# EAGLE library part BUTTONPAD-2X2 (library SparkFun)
5mm Button Pad Proven layout and schematic for 2x2 button pad. Panelize this device/fp to a 4x4 pad if needed. Spark Fun Electronics SKU : COM-07835. Compatible common cathode tri-color LED SKU : COM-00105

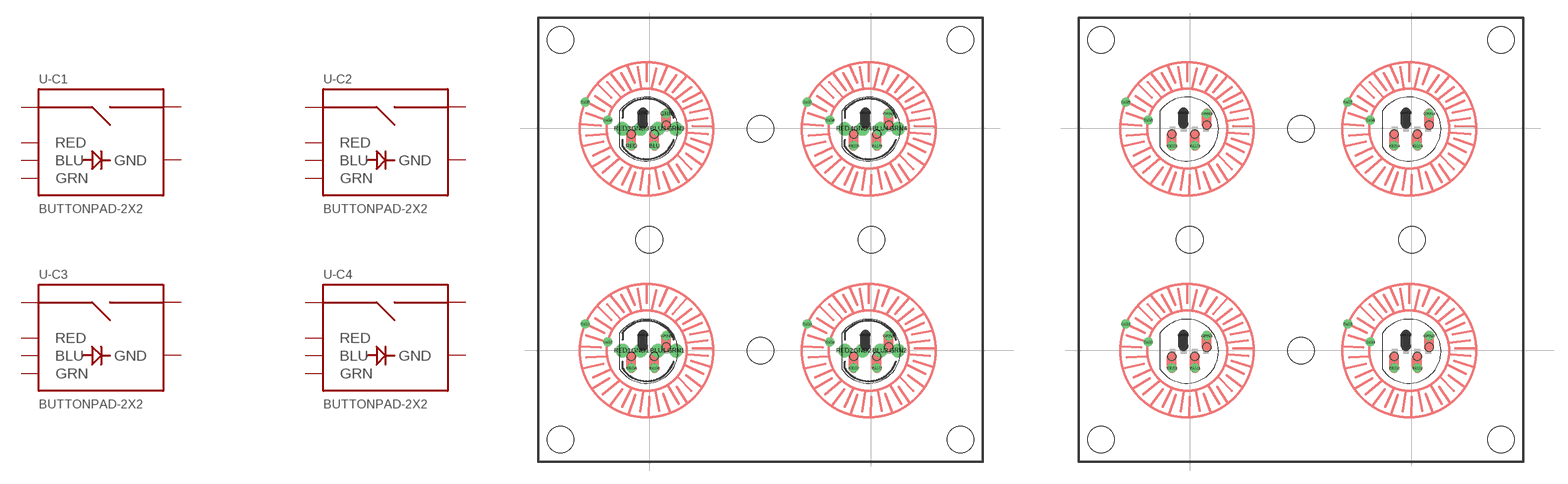
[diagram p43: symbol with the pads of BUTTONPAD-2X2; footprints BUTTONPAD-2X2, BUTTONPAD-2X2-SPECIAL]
Designator prefix -; gates -C1=BUTTONPAD_SINGLE -C2=BUTTONPAD_SINGLE -C3=BUTTONPAD_SINGLE -C4=BUTTONPAD_SINGLE

## BUTTONPAD-2X2  [BUTTONPAD-2X2]
BLU1  -C1:BLU
BLU2  -C2:BLU
BLU3  -C3:BLU
BLU4  -C4:BLU
GND1  -C1:GND
GND2  -C2:GND
GND3  -C3:GND
GND4  -C4:GND
GRN1  -C1:GRN
GRN2  -C2:GRN
GRN3  -C3:GRN
GRN4  -C4:GRN
RED1  -C1:RED
RED2  -C2:RED
RED3  -C3:RED
RED4  -C4:RED
SIG1  -C1:SIG1
SIG2  -C1:SIG2
SIG3  -C2:SIG1
SIG4  -C2:SIG2
SIG5  -C3:SIG1
SIG6  -C3:SIG2
SIG7  -C4:SIG1
SIG8  -C4:SIG2

## BUTTONPAD-2X2-SPECIAL  [BUTTONPAD-2X2-SPECIAL]
Pads as for BUTTONPAD-2X2

## Footprint BUTTONPAD-2X2 (pad centres in mm)
drill 0.508 round: BLU 13.081,35.585; BLU5 38.1,35.585; BLU6 13.081,10.566; BLU7 38.1,10.566; GND 11.786,39.319; GND5 36.805,39.319; GND6 11.786,14.3; GND7 36.805,14.3; GRN 14.427,39.218; GRN5 39.446,39.218; GRN6 14.427,14.199; GRN7 39.446,14.199; RED 10.49,35.585; RED5 35.509,35.585; RED6 10.49,10.566; RED7 35.509,10.566; SIG1 5.288,15.513; SIG2 7.828,13.481; SIG3 30.288,15.513; SIG4 32.828,13.481; SIG5 5.288,40.513; SIG6 7.828,38.481; SIG7 30.288,40.513; SIG8 32.828,38.481
drill 1 round: BLU1 13.5,12.5; BLU2 38.5,12.5; BLU3 13.5,37.5; BLU4 38.5,37.5; GND1 11.5,12.5; GND2 36.5,12.5; GND3 11.5,37.5; GND4 36.5,37.5; GRN1 15.5,12.5; GRN2 40.5,12.5; GRN3 15.5,37.5; GRN4 40.5,37.5; RED1 9.5,12.5; RED2 34.5,12.5; RED3 9.5,37.5; RED4 34.5,37.5
hole 3 at 12.5,25
hole 3 at 25,37.5
hole 3 at 37.5,25
hole 3 at 25,12.5
hole 3 at 2.5,2.5
hole 3 at 2.5,47.5
hole 3 at 47.5,47.5
hole 3 at 47.5,2.5
hole 0.914 at 10.49,36.881
hole 0.914 at 11.786,38.024
hole 0.914 at 13.081,36.881
hole 0.914 at 14.427,37.922
hole 0.914 at 35.509,36.881
hole 0.914 at 36.805,38.024
hole 0.914 at 38.1,36.881
hole 0.914 at 39.446,37.922
hole 0.914 at 10.49,11.862
hole 0.914 at 11.786,13.005
hole 0.914 at 13.081,11.862
hole 0.914 at 14.427,12.903
hole 0.914 at 35.509,11.862
hole 0.914 at 36.805,13.005
hole 0.914 at 38.1,11.862
hole 0.914 at 39.446,12.903

## Footprint BUTTONPAD-2X2-SPECIAL (pad centres in mm)
drill 0.508 round: BLU1 13.081,10.566; BLU2 38.1,10.566; BLU3 13.081,35.585; BLU4 38.1,35.585; GND1 11.786,14.3; GND2 36.805,14.3; GND3 11.786,39.319; GND4 36.805,39.319; GRN1 14.427,14.199; GRN2 39.446,14.199; GRN3 14.427,39.218; GRN4 39.446,39.218; RED1 10.49,10.566; RED2 35.509,10.566; RED3 10.49,35.585; RED4 35.509,35.585; SIG1 5.288,15.513; SIG2 7.828,13.481; SIG3 30.288,15.513; SIG4 32.828,13.481; SIG5 5.288,40.513; SIG6 7.828,38.481; SIG7 30.288,40.513; SIG8 32.828,38.481
hole 3 at 12.5,25
hole 3 at 25,37.5
hole 3 at 37.5,25
hole 3 at 25,12.5
hole 3 at 2.5,2.5
hole 3 at 2.5,47.5
hole 3 at 47.5,47.5
hole 3 at 47.5,2.5
hole 0.914 at 10.49,36.881
hole 0.914 at 11.786,38.024
hole 0.914 at 13.081,36.881
hole 0.914 at 14.427,37.922
hole 0.914 at 35.509,36.881
hole 0.914 at 36.805,38.024
hole 0.914 at 38.1,36.881
hole 0.914 at 39.446,37.922
hole 0.914 at 10.49,11.862
hole 0.914 at 11.786,13.005
hole 0.914 at 13.081,11.862
hole 0.914 at 14.427,12.903
hole 0.914 at 35.509,11.862
hole 0.914 at 36.805,13.005
hole 0.914 at 38.1,11.862
hole 0.914 at 39.446,12.903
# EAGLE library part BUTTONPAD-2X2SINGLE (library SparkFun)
5mm Button Pad Proto layout and schematic for 2x2 button pad with single color LEDs (used on Simon board). Panelize this device/fp to a 4x4 pad if needed. Any single-color 5mm LED should be compatible. Spark Fun Electronics SKU : COM-07835.

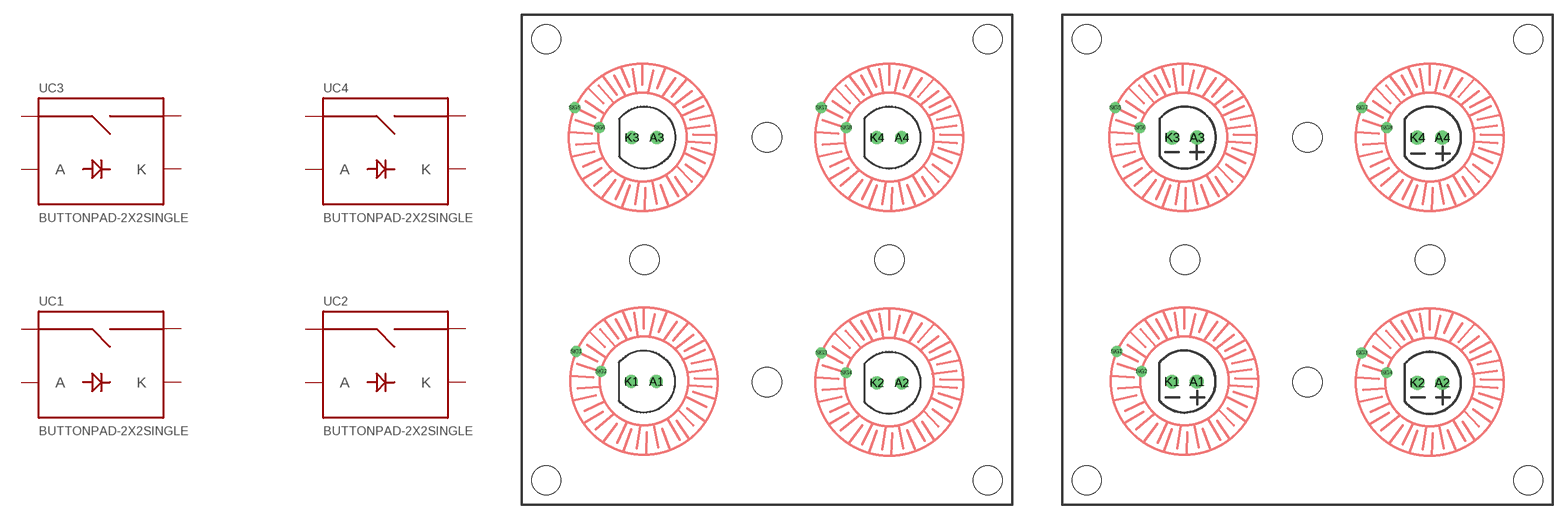
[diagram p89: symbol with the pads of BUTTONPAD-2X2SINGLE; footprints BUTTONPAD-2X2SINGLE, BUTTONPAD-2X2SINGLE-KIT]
Designator prefix -; gates C1=BUTTONPAD_1LED C2=BUTTONPAD_1LED C3=BUTTONPAD_1LED C4=BUTTONPAD_1LED

## BUTTONPAD-2X2SINGLE  [BUTTONPAD-2X2SINGLE]
A1  C1:A
A2  C2:A
A3  C3:A
A4  C4:A
K1  C1:K
K2  C2:K
K3  C3:K
K4  C4:K
SIG1  C1:SIG1
SIG2  C1:SIG2
SIG3  C2:SIG1
SIG4  C2:SIG2
SIG5  C3:SIG1
SIG6  C3:SIG2
SIG7  C4:SIG1
SIG8  C4:SIG2

## BUTTONPAD-2X2SINGLEKIT  [BUTTONPAD-2X2SINGLE-KIT]
Pads as for BUTTONPAD-2X2SINGLE

## Footprint BUTTONPAD-2X2SINGLE (pad centres in mm)
drill 0.813 round: A1 13.716,12.573; A2 38.735,12.446; A3 13.75,37.47; A4 38.735,37.465; K1 11.176,12.573; K2 36.195,12.446; K3 11.21,37.47; K4 36.195,37.465
drill 0.6 round: SIG1 5.542,15.64; SIG2 8.082,13.608; SIG3 30.542,15.513; SIG4 33.082,13.481; SIG5 5.388,40.513; SIG6 7.928,38.481; SIG7 30.542,40.513; SIG8 33.082,38.481
hole 3 at 12.5,25
hole 3 at 25,37.5
hole 3 at 37.5,25
hole 3 at 25,12.5
hole 3 at 2.5,2.5
hole 3 at 2.5,47.5
hole 3 at 47.5,47.5
hole 3 at 47.5,2.5

## Footprint BUTTONPAD-2X2SINGLE-KIT (pad centres in mm)
BUTTONPAD-2X2SINGLE-KIT Warning: This is the KIT version of this package. This package has a smaller diameter top stop mask, which doesn't cover the diameter of the pad. This means only the bottom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
drill 0.889 pad 1.016 round: A1 13.716,12.573; A2 38.735,12.446; A3 13.75,37.47; A4 38.735,37.465; K1 11.176,12.573; K2 36.195,12.446; K3 11.21,37.47; K4 36.195,37.465
drill 0.6 round: SIG1 5.542,15.64; SIG2 8.082,13.608; SIG3 30.542,15.513; SIG4 33.082,13.481; SIG5 5.388,40.513; SIG6 7.928,38.481; SIG7 30.542,40.513; SIG8 33.082,38.481
hole 3 at 12.5,25
hole 3 at 25,37.5
hole 3 at 37.5,25
hole 3 at 25,12.5
hole 3 at 2.5,2.5
hole 3 at 2.5,47.5
hole 3 at 47.5,47.5
hole 3 at 47.5,2.5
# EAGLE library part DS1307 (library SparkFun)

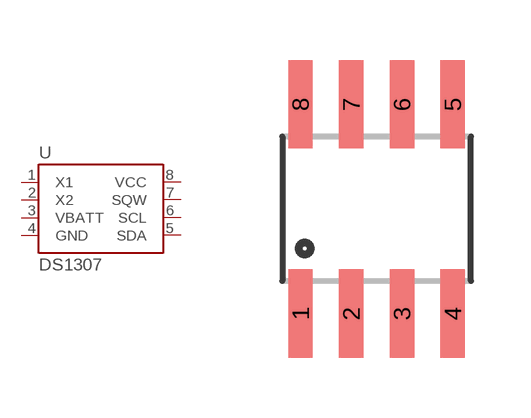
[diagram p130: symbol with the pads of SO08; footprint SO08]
Designator prefix -

## DS1307SO8  [SO08]
1  X1
2  X2
3  VBATT
4  GND
5  SDA
6  SCL
7  SQW
8  VCC

## Footprint SO08 (pad centres in mm)
Small Outline Package Fits JEDEC packages (narrow SOIC-8)
smd 0.61 x 2.21: 1 -1.905,-2.616; 2 -0.635,-2.616; 3 0.635,-2.616; 4 1.905,-2.616; 5 1.905,2.616; 6 0.635,2.616; 7 -0.635,2.616; 8 -1.905,2.616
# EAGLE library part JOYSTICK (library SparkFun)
Thumb Joystick Joystick commonly found in PS2 controllers. Two pots and a select switch. Footprint proven. Spark Fun Electronics SKU : COM-09032

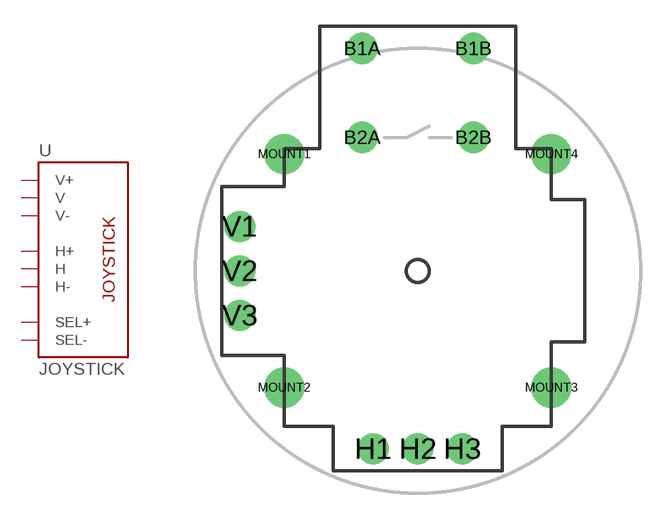
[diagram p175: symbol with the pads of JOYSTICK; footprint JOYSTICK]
Designator prefix U

## JOYSTICKPTH  [JOYSTICK]
B1A  SEL+
B2A  SEL-
H1  H+
H2  H
H3  H-
V1  V+
V2  V
V3  V-

## Footprint JOYSTICK (pad centres in mm)
drill 0.9 pad 1.778 round: B1A -3.175,12.7; B1B 3.175,12.7; B2A -3.175,7.62; B2B 3.175,7.62
drill 0.889 pad 1.778 round: H1 -2.54,-10.16; H2 0,-10.16; H3 2.54,-10.16; V1 -10.16,2.54; V2 -10.16,0; V3 -10.16,-2.54
drill 1.397 pad 2.286 round: MOUNT1 -7.62,6.668; MOUNT2 -7.62,-6.668; MOUNT3 7.62,-6.668; MOUNT4 7.62,6.668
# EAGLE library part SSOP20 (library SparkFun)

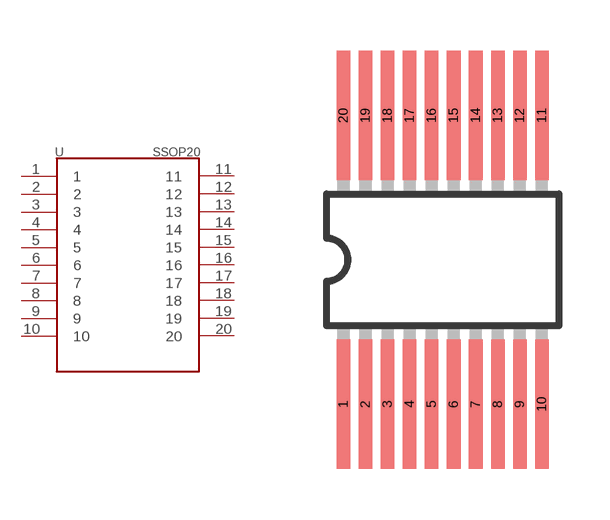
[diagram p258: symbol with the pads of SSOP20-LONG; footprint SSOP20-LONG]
Designator prefix -

## SSOP20  [SSOP20-LONG]
1  1
2  2
3  3
4  4
5  5
6  6
7  7
8  8
9  9
10  10
11  11
12  12
13  13
14  14
15  15
16  16
17  17
18  18
19  19
20  20

## Footprint SSOP20-LONG (pad centres in mm)
SSOP-20PIN Do Not Use as this is for the silkscreen of the breakout board for 20pin-SSOP ICs
smd 0.4 x 3.81: 1 -2.925,-4.26; 2 -2.275,-4.26; 3 -1.625,-4.26; 4 -0.975,-4.26; 5 -0.325,-4.26; 6 0.325,-4.26; 7 0.975,-4.26; 8 1.625,-4.26; 9 2.275,-4.26; 10 2.925,-4.26; 11 2.925,4.26; 12 2.275,4.26; 13 1.625,4.26; 14 0.975,4.26; 15 0.325,4.26; 16 -0.325,4.26; 17 -0.975,4.26; 18 -1.625,4.26; 19 -2.275,4.26; 20 -2.925,4.26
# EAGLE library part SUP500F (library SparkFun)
SUP500F Venus GPS

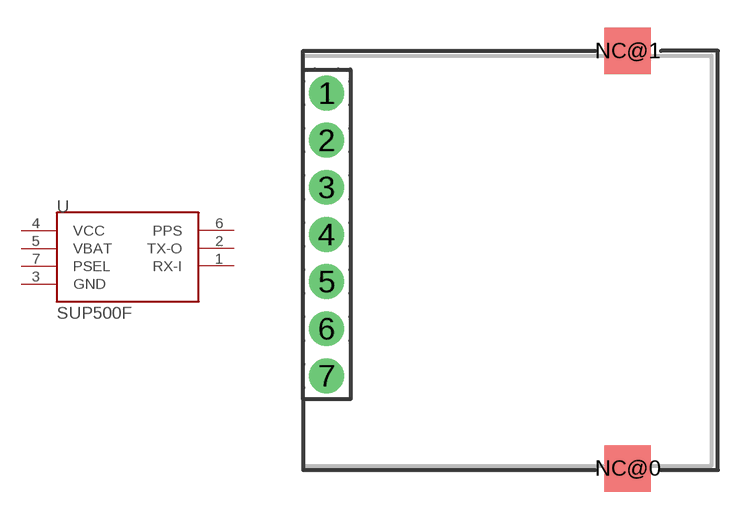
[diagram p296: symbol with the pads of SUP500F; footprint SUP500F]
Designator prefix U

## SUP500F  [SUP500F]
1  RX-I
2  TX-O
3  GND
4  VCC
5  VBAT
6  PPS
7  PSEL

## Footprint SUP500F (pad centres in mm)
drill 1.016 pad 1.88 round: 1 0,15.24; 2 0,12.7; 3 0,10.16; 4 0,7.62; 5 0,5.08; 6 0,2.54; 7 0,0
smd 2.5 x 2.5: NC@0 16.22,-5; NC@1 16.22,17.51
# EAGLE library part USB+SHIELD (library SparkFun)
USB+Shield USB connector with shield pins connectable

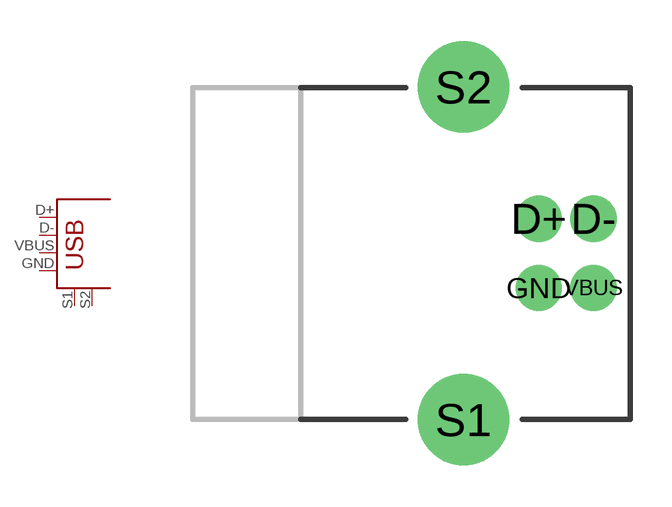
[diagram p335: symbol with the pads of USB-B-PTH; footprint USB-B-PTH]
Designator prefix -

## USB+SHIELD  [USB-B-PTH]
D+  D+
D-  D-
GND  GND
S1  P$1
S2  P$2
VBUS  VBUS

## Footprint USB-B-PTH (pad centres in mm)
USB Series B Hole Mounted
drill 0.914 pad 1.676 round: D+ 0,1.25; D- 1.981,1.25; GND 0,-1.25; VBUS 1.981,-1.25
drill 2.286 round: S1 -2.718,-6.02; S2 -2.718,6.02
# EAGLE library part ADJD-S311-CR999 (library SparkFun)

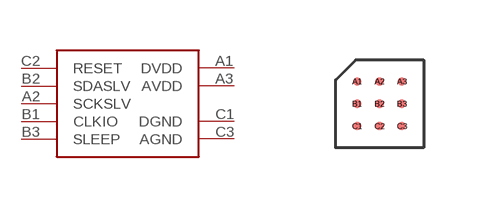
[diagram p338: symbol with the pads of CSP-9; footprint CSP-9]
Designator prefix -

## ADJD-S311-CR999  [CSP-9]
A1  DVDD
A2  SCKSLV
A3  AVDD
B1  CLKIO
B2  SDASLV
B3  SLEEP
C1  DGND
C2  RESET
C3  AGND

## Footprint CSP-9 (pad centres in mm)
smd 0.21 x 0.21: A1 -0.56,0.56; A2 0,0.56; A3 0.56,0.56; B1 -0.56,0; B2 0,0; B3 0.56,0; C1 -0.56,-0.56; C2 0,-0.56; C3 0.56,-0.56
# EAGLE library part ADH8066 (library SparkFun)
8066-GSM-GPRS module from ADH-Tech

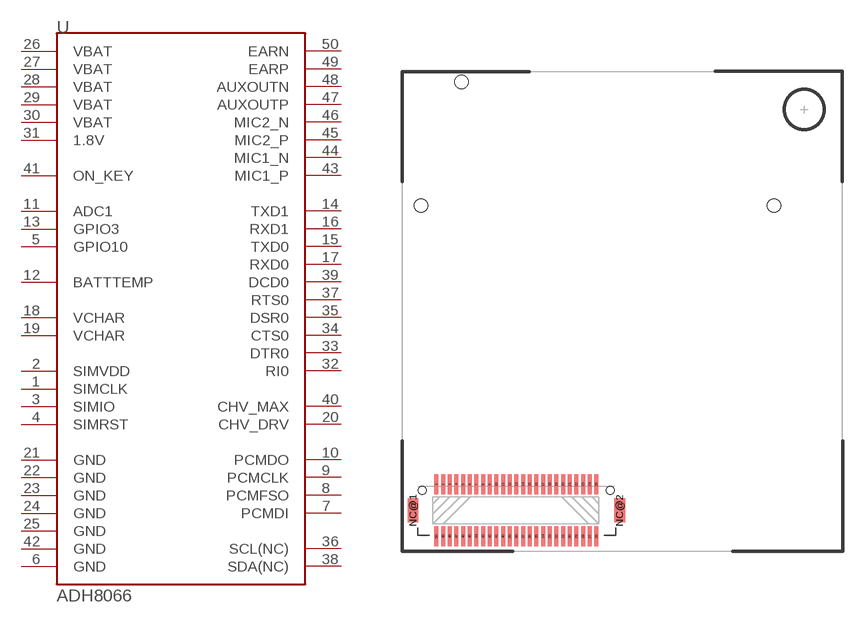
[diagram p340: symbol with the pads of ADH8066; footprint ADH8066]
Designator prefix U

## ADH8066_SMD  [ADH8066]
1  SIMCLK
2  SIMVDD
3  SIMIO
4  SIMRST
5  GPIO10
6  GND
7  PCMDI
8  PCMFSO
9  PCMCLK
10  PCMDO
11  ADC1
12  BATTTEMP
13  GPIO3
14  TXD1
15  TXD0
16  RXD1
17  RXD0
18  VCHAR
19  VCHAR
20  CHV_DRV
21  GND
22  GND
23  GND
24  GND
25  GND
26  VBAT
27  VBAT
28  VBAT
29  VBAT
30  VBAT
31  1.8V
32  RI0
33  DTR0
34  CTS0
35  DSR0
36  SCL(NC)
37  RTS0
38  SDA(NC)
39  DCD0
40  CHV_MAX
41  ON_KEY
42  GND
43  MIC1_P
44  MIC1_N
45  MIC2_P
46  MIC2_N
47  AUXOUTP
48  AUXOUTN
49  EARP
50  EARN

## Footprint ADH8066 (pad centres in mm)
FP for ADH8066 cell modules. Uses 50-pin connector with 0.5mm pitch Hirose part# DF12(3.0)-50DP-0.5V
smd 0.3 x 1.5: 1 2.55,5; 2 3.05,5; 3 3.55,5; 4 4.05,5; 5 4.55,5; 6 5.05,5; 7 5.55,5; 8 6.05,5; 9 6.55,5; 10 7.05,5; 11 7.55,5; 12 8.05,5; 13 8.55,5; 14 9.05,5; 15 9.55,5; 16 10.05,5; 17 10.55,5; 18 11.05,5; 19 11.55,5; 20 12.05,5; 21 12.55,5; 22 13.05,5; 23 13.55,5; 24 14.05,5; 25 14.55,5; 26 14.55,1.1; 27 14.05,1.1; 28 13.55,1.1; 29 13.05,1.1; 30 12.55,1.1; 31 12.05,1.1; 32 11.55,1.1; 33 11.05,1.1; 34 10.55,1.1; 35 10.05,1.1; 36 9.55,1.1; 37 9.05,1.1; 38 8.55,1.1; 39 8.05,1.1; 40 7.55,1.1; 41 7.05,1.1; 42 6.55,1.1; 43 6.05,1.1; 44 5.55,1.1; 45 5.05,1.1; 46 4.55,1.1; 47 4.05,1.1; 48 3.55,1.1; 49 3.05,1.1; 50 2.55,1.1
smd 0.8 x 1.8: NC@1 0.8,3.05; NC@2 16.3,3.05
hole 0.6 at 15.6,4.55
hole 0.6 at 1.5,4.55
hole 1 at 4.43,35.24
hole 1 at 1.38,25.94
hole 1 at 27.88,25.94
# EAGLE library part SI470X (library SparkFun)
Description: This is a powerful FM receiver IC. Tested with Si4703. You really only need SEN, RST, SCLK, and SDIO to get a full FM radio working. Antenna comes from headphone jack. See breakout board on SparkFun website for more information.

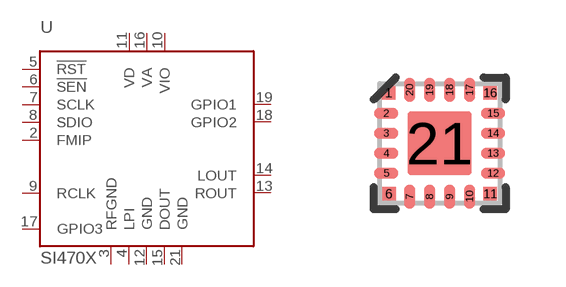
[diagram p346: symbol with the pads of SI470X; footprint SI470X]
Designator prefix U

## SI470X  [SI470X]
2  FMIP
3  RFGND
4  LPI
5  !RST
6  !SEN
7  SCLK
8  SDIO
9  RCLK
10  VIO
11  VD
12  GND
13  ROUT
14  LOUT
15  DOUT
16  VA
17  GPIO3
18  GPIO2
19  GPIO1
21  GND

## Footprint SI470X (pad centres in mm)
smd 0.34 x 0.34: 1 -1.275,1.265; 6 -1.265,-1.265; 11 1.265,-1.265; 16 1.265,1.265
smd 0.61 x 0.28: 2 -1.335,0.75; 3 -1.335,0.25; 4 -1.335,-0.25; 5 -1.335,-0.75; 12 1.335,-0.75; 13 1.335,-0.25; 14 1.335,0.25; 15 1.335,0.75
smd 0.28 x 0.61: 7 -0.75,-1.335; 8 -0.25,-1.335; 9 0.25,-1.335; 10 0.75,-1.335; 17 0.75,1.335; 18 0.25,1.335; 19 -0.25,1.335; 20 -0.75,1.335
smd 1.6 x 1.6: 21 0,0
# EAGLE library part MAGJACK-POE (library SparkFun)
PoE compatible MagJack

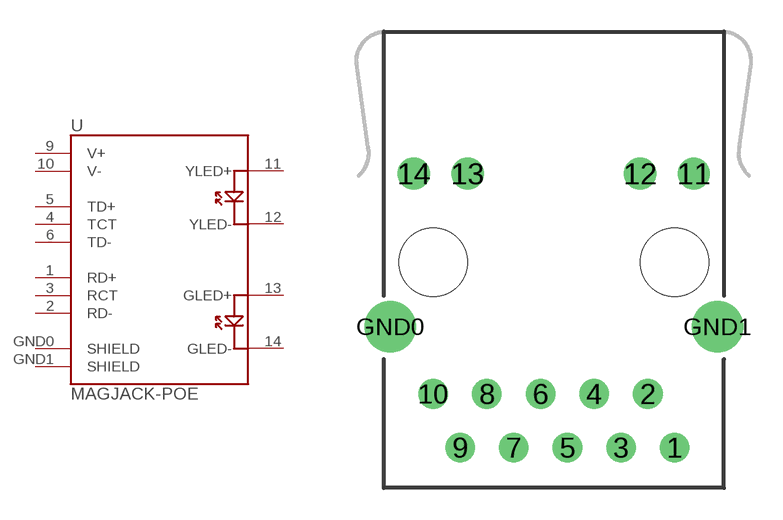
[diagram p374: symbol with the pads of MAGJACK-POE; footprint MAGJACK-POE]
Designator prefix U

## MAGJACK-POE  [MAGJACK-POE]
1  RD+
2  RD-
3  RCT
4  TCT
5  TD+
6  TD-
9  V+
10  V-
11  YLED+
12  YLED-
13  GLED+
14  GLED-
GND0  SHIELD
GND1  SHIELD

## Footprint MAGJACK-POE (pad centres in mm)
PoE Compatible MagJack This RJ-45 jack with magnetics has 10 pins, gives you access to the unused twisted pair (10BASE-T, and 100BASE-T) which usually carries power in a power-over-ethernet system.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
drill 0.89 round: 1 5.72,-8.89; 2 4.45,-6.35; 3 3.18,-8.89; 4 1.91,-6.35; 5 0.64,-8.89; 6 -0.63,-6.35; 7 -1.9,-8.89; 8 -3.17,-6.35; 9 -4.44,-8.89; 10 -5.71,-6.35
drill 1.02 round: 11 6.625,4.08; 12 4.085,4.08; 13 -4.085,4.08; 14 -6.625,4.08
drill 1.63 round: GND0 -7.745,-3.17; GND1 7.745,-3.17
hole 3.25 at -5.715,-0.12
hole 3.25 at 5.715,-0.12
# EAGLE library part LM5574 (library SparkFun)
LM5574 Simple Switcher 75V, 0.5A Step-down switching regulator

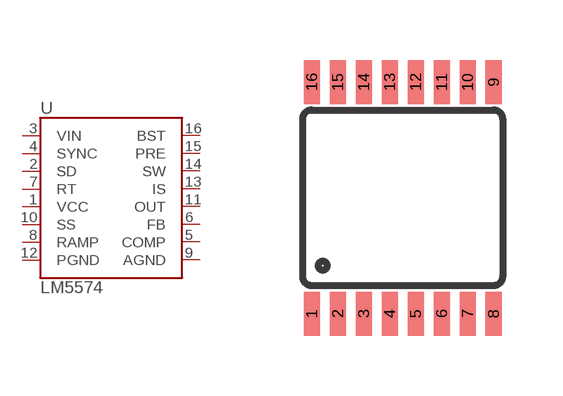
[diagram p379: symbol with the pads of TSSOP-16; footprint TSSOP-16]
Designator prefix U

## LM5574  [TSSOP-16]
1  VCC
2  SD
3  VIN
4  SYNC
5  COMP
6  FB
7  RT
8  RAMP
9  AGND
10  SS
11  OUT
12  PGND
13  IS
14  SW
15  PRE
16  BST

## Footprint TSSOP-16 (pad centres in mm)
smd 0.4 x 1.1: 1 -2.275,-2.9; 2 -1.625,-2.9; 3 -0.975,-2.9; 4 -0.325,-2.9; 5 0.325,-2.9; 6 0.975,-2.9; 7 1.625,-2.9; 8 2.275,-2.9; 9 2.275,2.9; 10 1.625,2.9; 11 0.975,2.9; 12 0.325,2.9; 13 -0.325,2.9; 14 -0.975,2.9; 15 -1.625,2.9; 16 -2.275,2.9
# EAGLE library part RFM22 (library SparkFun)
Description: The RFM22 is a low-power, low cost radio that is capable of operating in the 434MHz and 900MHz open bands. It's frequency is software defined and there are some very good libraries written for it.

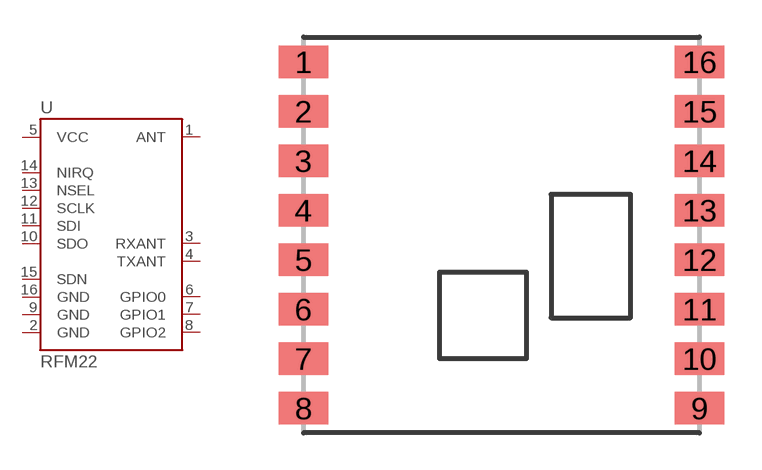
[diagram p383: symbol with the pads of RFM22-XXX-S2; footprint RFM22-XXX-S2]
Designator prefix -

## RFM22SMD  [RFM22-XXX-S2]
1  ANT
2  GND  pwr
3  RXANT  in
4  TXANT  in
5  VCC
6  GPIO0
7  GPIO1
8  GPIO2
9  GND  pwr
10  SDO  out
11  SDI  in
12  SCLK  in
13  NSEL  in
14  NIRQ  out
15  SDN  in
16  GND  pwr

## Footprint RFM22-XXX-S2 (pad centres in mm)
Package for Hope RF s RFM22-xxx-S2 SMD wireless transciever, xxx is module s frequency band. *Unproven*''
smd 2 x 1.3: 1 -8,7; 2 -8,5; 3 -8,3; 4 -8,1; 5 -8,-1; 6 -8,-3; 7 -8,-5; 8 -8,-7; 9 8,-7; 10 8,-5; 11 8,-3; 12 8,-1; 13 8,1; 14 8,3; 15 8,5; 16 8,7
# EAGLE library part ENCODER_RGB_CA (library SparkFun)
Illuminated Rotary Encoder w/ RGB LED and select switch EC12PLRGBSDVBF-D: http://top-up.so-buy.com/front/bin/ptdetail.phtml?Part=EC12PLRGBSDVBF-D

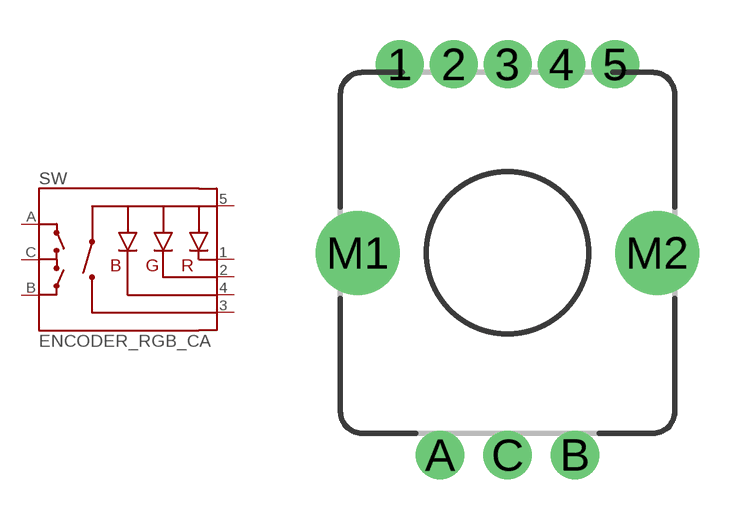
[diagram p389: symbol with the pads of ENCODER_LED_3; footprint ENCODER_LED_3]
Designator prefix SW

## ENCODER_RGB_CA  [ENCODER_LED_3]
1  -R  pas
2  -G  pas
3  SW  pas
4  -B  pas
5  +  pas
A  A
B  B
C  C

## Footprint ENCODER_LED_3 (pad centres in mm)
drill 1.1 pad 1.778 round: 1 -4,7; 2 -2,7; 3 0,7; 4 2,7; 5 4,7
drill 1.1 pad 1.8 round: A -2.5,-7.5; B 2.5,-7.5; C 0,-7.5
drill 2.1 round: M1 -5.55,0; M2 5.55,0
